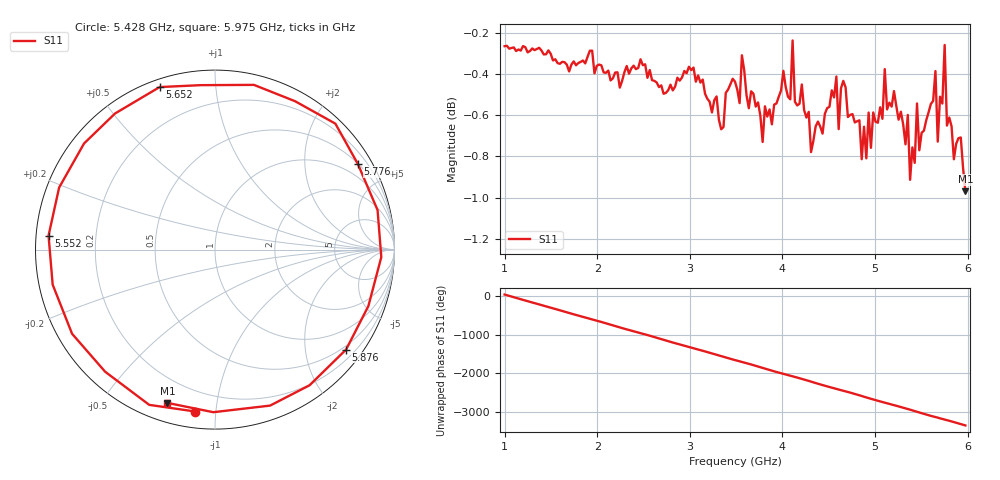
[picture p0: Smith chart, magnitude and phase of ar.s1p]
# Hz S RI R 50
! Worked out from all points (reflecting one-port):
!   201 points, 1 GHz to 5.975 GHz, reference 50 ohm
!   lowest |S11| = -1.0 dB at 5.975 GHz (marker M1), VSWR 17.92, Z = 4.3 - j36.7 ohm
!   phase of S11 starts at 38 deg and turns -3386 deg over the sweep
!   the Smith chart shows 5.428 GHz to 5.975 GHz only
!   S11 on the Smith chart (normalised r, x): 5.428 GHz: 0.09, -0.88; 5.552 GHz: 0.04, +0.04; 5.652 GHz: 0.03, +0.72; 5.776 GHz: 0.52, +3.55; 5.876 GHz: 0.41, -2.91; 5.975 GHz: 0.09, -0.73
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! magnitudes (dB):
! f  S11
! 1 GHz  -0.3
! 1.622 GHz  -0.3
! 2.244 GHz  -0.5
! 2.866 GHz  -0.4
! 3.338 GHz  -0.7
! 3.488 GHz  -0.4
! 3.786 GHz  -0.7
! 4.085 GHz  -0.5
! 4.109 GHz  -0.2
! 4.134 GHz  -0.5
! 4.308 GHz  -0.8
! 4.582 GHz  -0.4
! 4.607 GHz  -0.7
! 4.731 GHz  -0.6
! 4.905 GHz  -0.8
! 5.104 GHz  -0.4
! 5.353 GHz  -0.6
! 5.378 GHz  -0.9
! 5.428 GHz  -0.8
! 5.453 GHz  -0.5
! 5.478 GHz  -0.8
! 5.552 GHz  -0.6
! 5.652 GHz  -0.4
! 5.677 GHz  -0.7
! 5.751 GHz  -0.3
! 5.776 GHz  -0.7
! 5.876 GHz  -0.7
! 5.975 GHz  -1.0
